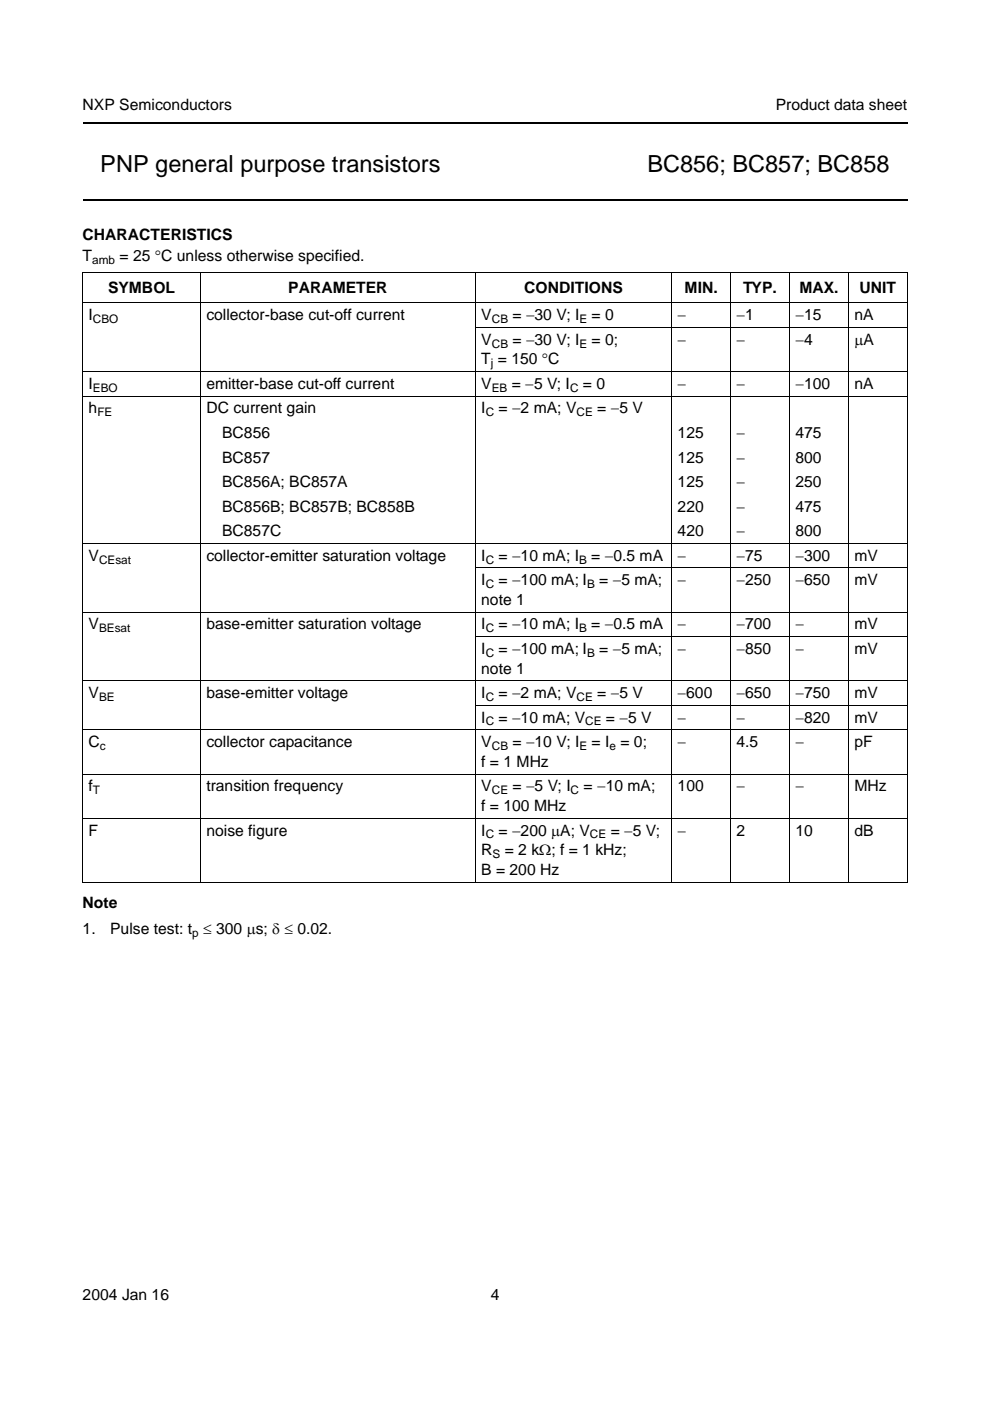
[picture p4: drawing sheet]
<svg xmlns="http://www.w3.org/2000/svg" width="210mm" height="297mm" viewBox="0 0 210 297" stroke-linecap="round" stroke-linejoin="round" font-family="sans-serif">
<defs><g id="words">
<g font-size="5">
<text x="21.3" y="36.4">PNP general purpose transistors</text>
<text x="137.3" y="36.4">BC856; BC857; BC858</text>
</g>
<g font-size="3.3">
<text x="17.5" y="23.3">NXP Semiconductors</text>
<text x="164.5" y="23.3">Product data sheet</text>
<text x="17.5" y="50.8">CHARACTERISTICS</text>
<text x="17.5" y="55.4">T</text>
<text x="25.4" y="55.4">= 25 °C unless otherwise specified.</text>
<text x="22.9" y="62.2">SYMBOL</text>
<text x="61.1" y="62.2">PARAMETER</text>
<text x="111.2" y="62.2">CONDITIONS</text>
<text x="145.2" y="62.2">MIN.</text>
<text x="157.6" y="62.2">TYP.</text>
<text x="169.5" y="62.2">MAX.</text>
<text x="182.2" y="62.2">UNIT</text>
<text x="18.8" y="67.9">I</text>
<text x="43.8" y="67.9">collector-base cut-off current</text>
<text x="102" y="67.9">V</text>
<text x="108.6" y="67.9">= −30 V; I</text>
<text x="125.4" y="67.9">= 0</text>
<text x="143.7" y="67.9">−</text>
<text x="156.2" y="67.9">−1</text>
<text x="168.7" y="67.9">−15</text>
<text x="181.1" y="67.9">nA</text>
<text x="102" y="77.3">T = 150 °C</text>
<text x="102" y="73.1">V</text>
<text x="108.6" y="73.1">= −30 V; I</text>
<text x="125.4" y="73.1">= 0;</text>
<text x="143.7" y="73.1">−</text>
<text x="156.2" y="73.1">−</text>
<text x="168.7" y="73.1">−4</text>
<text x="181.1" y="73.1">μA</text>
<text x="18.8" y="82.4">I</text>
<text x="43.8" y="82.4">emitter-base cut-off current</text>
<text x="102" y="82.4">V</text>
<text x="108.5" y="82.4">= −5 V; I</text>
<text x="123.6" y="82.4">= 0</text>
<text x="143.7" y="82.4">−</text>
<text x="156.2" y="82.4">−</text>
<text x="168.7" y="82.4">−100</text>
<text x="181.1" y="82.4">nA</text>
<text x="18.8" y="87.7">h</text>
<text x="43.8" y="87.7">DC current gain</text>
<text x="102" y="87.7">I</text>
<text x="105.7" y="87.7">= −2 mA; V</text>
<text x="126.6" y="87.7">= −5 V</text>
<text x="47.1" y="92.9">BC856</text>
<text x="143.7" y="92.9">125</text>
<text x="156.2" y="92.9">−</text>
<text x="168.7" y="92.9">475</text>
<text x="47.1" y="98.1">BC857</text>
<text x="143.7" y="98.1">125</text>
<text x="156.2" y="98.1">−</text>
<text x="168.7" y="98.1">800</text>
<text x="47.1" y="103.3">BC856A; BC857A</text>
<text x="143.7" y="103.3">125</text>
<text x="156.2" y="103.3">−</text>
<text x="168.7" y="103.3">250</text>
<text x="47.1" y="108.5">BC856B; BC857B; BC858B</text>
<text x="47.1" y="113.7">BC857C</text>
<text x="143.7" y="108.5">220</text>
<text x="143.7" y="113.7">420</text>
<text x="156.2" y="108.5">−</text>
<text x="156.2" y="113.7">−</text>
<text x="168.7" y="108.5">475</text>
<text x="168.7" y="113.7">800</text>
<text x="18.8" y="118.9">V</text>
<text x="43.8" y="118.9">collector-emitter saturation voltage</text>
<text x="102" y="118.9">I</text>
<text x="105.7" y="118.9">= −10 mA; I</text>
<text x="125.4" y="118.9">= −0.5 mA</text>
<text x="143.7" y="118.9">−</text>
<text x="156.2" y="118.9">−75</text>
<text x="168.7" y="118.9">−300</text>
<text x="181.1" y="118.9">mV</text>
<text x="102" y="124.1">I</text>
<text x="105.7" y="124.1">= −100 mA; I</text>
<text x="127" y="124.1">= −5 mA;</text>
<text x="143.7" y="124.1">−</text>
<text x="156.2" y="124.1">−250</text>
<text x="168.7" y="124.1">−650</text>
<text x="181.1" y="124.1">mV</text>
<text x="102" y="128.2">note 1</text>
<text x="18.8" y="133.5">V</text>
<text x="43.8" y="133.5">base-emitter saturation voltage</text>
<text x="102" y="133.5">I</text>
<text x="105.7" y="133.5">= −10 mA; I</text>
<text x="125.4" y="133.5">= −0.5 mA</text>
<text x="143.7" y="133.5">−</text>
<text x="156.2" y="133.5">−700</text>
<text x="168.7" y="133.5">−</text>
<text x="181.1" y="133.5">mV</text>
<text x="102" y="142.8">note 1</text>
<text x="102" y="138.7">I</text>
<text x="105.7" y="138.7">= −100 mA; I</text>
<text x="127" y="138.7">= −5 mA;</text>
<text x="143.7" y="138.7">−</text>
<text x="156.2" y="138.7">−850</text>
<text x="168.7" y="138.7">−</text>
<text x="181.1" y="138.7">mV</text>
<text x="18.8" y="148">V</text>
<text x="43.8" y="148">base-emitter voltage</text>
<text x="102" y="148">I</text>
<text x="105.7" y="148">= −2 mA; V</text>
<text x="126.6" y="148">= −5 V</text>
<text x="143.7" y="148">−600</text>
<text x="156.2" y="148">−650</text>
<text x="168.7" y="148">−750</text>
<text x="181.1" y="148">mV</text>
<text x="102" y="153.2">I</text>
<text x="105.7" y="153.2">= −10 mA; V</text>
<text x="128.5" y="153.2">= −5 V</text>
<text x="143.7" y="153.2">−</text>
<text x="156.2" y="153.2">−</text>
<text x="168.7" y="153.2">−820</text>
<text x="181.1" y="153.2">mV</text>
<text x="18.8" y="158.4">C</text>
<text x="43.8" y="158.4">collector capacitance</text>
<text x="102" y="158.4">V</text>
<text x="108.6" y="158.4">= −10 V; I</text>
<text x="125.4" y="158.4">= I = 0;</text>
<text x="143.7" y="158.4">−</text>
<text x="156.2" y="158.4">4.5</text>
<text x="168.7" y="158.4">−</text>
<text x="181.1" y="158.4">pF</text>
<text x="18.8" y="167.8">f</text>
<text x="43.8" y="167.8">transition frequency</text>
<text x="102" y="162.6">f = 1 MHz</text>
<text x="102" y="167.8">V</text>
<text x="108.6" y="167.8">= −5 V; I</text>
<text x="123.7" y="167.8">= −10 mA;</text>
<text x="143.7" y="167.8">100</text>
<text x="156.2" y="167.8">−</text>
<text x="168.7" y="167.8">−</text>
<text x="181.1" y="167.8">MHz</text>
<text x="102" y="172">f = 100 MHz</text>
<text x="18.8" y="177.2">F</text>
<text x="43.8" y="177.2">noise figure</text>
<text x="102" y="177.2">I</text>
<text x="105.7" y="177.2">= −200 μA; V</text>
<text x="129.5" y="177.2">= −5 V;</text>
<text x="143.7" y="177.2">−</text>
<text x="156.2" y="177.2">2</text>
<text x="168.7" y="177.2">10</text>
<text x="181.1" y="177.2">dB</text>
<text x="102" y="185.5">B = 200 Hz</text>
<text x="102" y="181.3">R</text>
<text x="107" y="181.3">= 2 kΩ; f = 1 kHz;</text>
<text x="17.5" y="192.6">Note</text>
<text x="17.5" y="198">1.</text>
<text x="23.4" y="198">Pulse test: t ≤ 300 μs; δ ≤ 0.02.</text>
<text x="17.5" y="275.6">2004 Jan 16</text>
<text x="104" y="275.6">4</text>
</g>
<g font-size="2.5">
<text x="19.6" y="56">amb</text>
<text x="19.7" y="68.5">CBO</text>
<text x="104.3" y="68.5">CB</text>
<text x="122.9" y="68.5">E</text>
<text x="104.1" y="77.9">j</text>
<text x="104.3" y="73.7">CB</text>
<text x="122.9" y="73.7">E</text>
<text x="19.7" y="83.1">EBO</text>
<text x="104.3" y="83.1">EB</text>
<text x="120.9" y="83.1">C</text>
<text x="20.6" y="88.3">FE</text>
<text x="103" y="88.3">C</text>
<text x="122.2" y="88.3">CE</text>
<text x="21" y="119.5">CEsat</text>
<text x="103" y="119.5">C</text>
<text x="122.8" y="119.5">B</text>
<text x="103" y="124.7">C</text>
<text x="124.5" y="124.7">B</text>
<text x="21" y="134">BEsat</text>
<text x="103" y="134">C</text>
<text x="122.8" y="134">B</text>
<text x="103" y="139.3">C</text>
<text x="124.5" y="139.3">B</text>
<text x="21" y="148.6">BE</text>
<text x="103" y="148.6">C</text>
<text x="122.2" y="148.6">CE</text>
<text x="103" y="153.8">C</text>
<text x="124.1" y="153.8">CE</text>
<text x="21.2" y="159">c</text>
<text x="104.3" y="159">CB</text>
<text x="122.9" y="159">E</text>
<text x="129.2" y="159">e</text>
<text x="19.7" y="168.4">T</text>
<text x="104.3" y="168.4">CE</text>
<text x="121" y="168.4">C</text>
<text x="103" y="177.8">C</text>
<text x="125.1" y="177.8">CE</text>
<text x="104.4" y="181.9">S</text>
<text x="40.7" y="198.6">p</text>
</g>
</g></defs>
<path d="M17.5 26.1h174.9M17.5 42.4h174.9" fill="none" stroke="#000" stroke-width=".42"/>
<g fill="none" stroke="#000" stroke-width=".21">
<path d="M17.4 57.9h175.1M17.5 58v128.9M42.5 57.8v129.3M100.8 57.8v129.3M142.4 57.8v129.3M154.9 57.8v129.3M167.4 57.8v129.3M179.9 57.8v129.3M192.4 58v128.9M17.4 64.2h175.1M17.4 78.8h175.1M100.7 69.4h91.8"/>
<path d="M17.4 84h175.1M17.4 115.2h175.1M17.4 129.8h175.1M100.7 120.4h91.8M100.7 135h91.8M17.4 144.3h175.1M17.4 154.7h175.1M100.7 149.5h91.8M17.4 164.1h175.1M17.4 173.5h175.1M17.4 187h175.1"/>
</g>
<use href="#words"/>
</svg>
